VERSION 5.7 ;
  NOWIREEXTENSIONATPIN ON ;
  DIVIDERCHAR "/" ;
  BUSBITCHARS "[]" ;
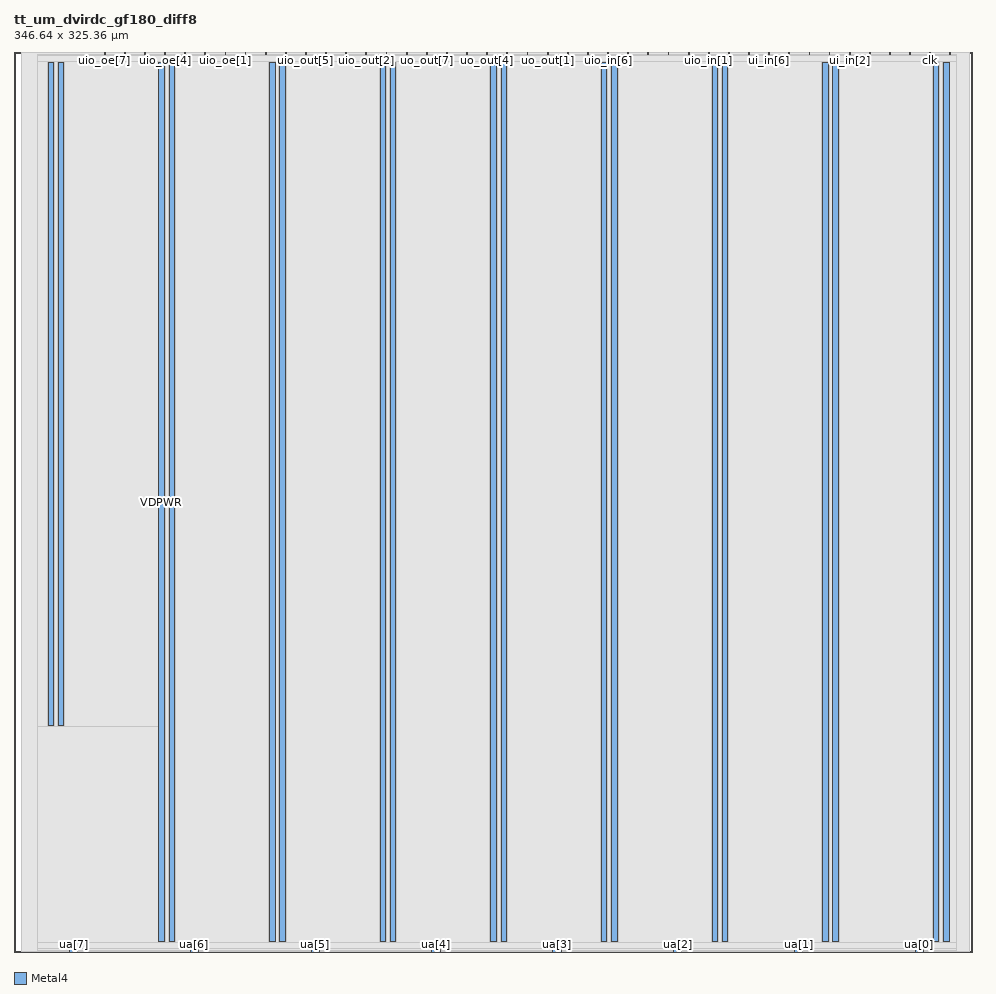
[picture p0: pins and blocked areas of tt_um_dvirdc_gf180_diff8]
MACRO tt_um_dvirdc_gf180_diff8
  CLASS BLOCK ;
  FOREIGN tt_um_dvirdc_gf180_diff8 ;
  ORIGIN 0.000 0.000 ;
  SIZE 346.640 BY 325.360 ;
  PIN VDPWR
    DIRECTION INOUT ;
    USE POWER ;
    PORT
      LAYER Metal4 ;
        RECT 12.360 81.800 14.360 321.740 ;
    END
    PORT
      LAYER Metal4 ;
        RECT 52.360 3.620 54.360 321.740 ;
    END
    PORT
      LAYER Metal4 ;
        RECT 92.360 3.620 94.360 321.740 ;
    END
    PORT
      LAYER Metal4 ;
        RECT 132.360 3.620 134.360 321.740 ;
    END
    PORT
      LAYER Metal4 ;
        RECT 172.360 3.620 174.360 321.740 ;
    END
    PORT
      LAYER Metal4 ;
        RECT 212.360 3.620 214.360 321.740 ;
    END
    PORT
      LAYER Metal4 ;
        RECT 252.360 3.620 254.360 321.740 ;
    END
    PORT
      LAYER Metal4 ;
        RECT 292.360 3.620 294.360 321.740 ;
    END
    PORT
      LAYER Metal4 ;
        RECT 332.360 3.620 334.360 321.740 ;
    END
  END VDPWR
  PIN VGND
    DIRECTION INOUT ;
    USE GROUND ;
    PORT
      LAYER Metal4 ;
        RECT 16.060 81.800 18.060 321.740 ;
    END
    PORT
      LAYER Metal4 ;
        RECT 56.060 3.620 58.060 321.740 ;
    END
    PORT
      LAYER Metal4 ;
        RECT 96.060 3.620 98.060 321.740 ;
    END
    PORT
      LAYER Metal4 ;
        RECT 136.060 3.620 138.060 321.740 ;
    END
    PORT
      LAYER Metal4 ;
        RECT 176.060 3.620 178.060 321.740 ;
    END
    PORT
      LAYER Metal4 ;
        RECT 216.060 3.620 218.060 321.740 ;
    END
    PORT
      LAYER Metal4 ;
        RECT 256.060 3.620 258.060 321.740 ;
    END
    PORT
      LAYER Metal4 ;
        RECT 296.060 3.620 298.060 321.740 ;
    END
    PORT
      LAYER Metal4 ;
        RECT 336.060 3.620 338.060 321.740 ;
    END
  END VGND
  PIN clk
    DIRECTION INPUT ;
    USE SIGNAL ;
    ANTENNAGATEAREA 0.726000 ;
    PORT
      LAYER Metal4 ;
        RECT 331.090 324.360 331.390 325.360 ;
    END
  END clk
  PIN ena
    DIRECTION INPUT ;
    USE SIGNAL ;
    ANTENNAGATEAREA 0.498500 ;
    PORT
      LAYER Metal4 ;
        RECT 338.370 324.360 338.670 325.360 ;
    END
  END ena
  PIN rst_n
    DIRECTION INPUT ;
    USE SIGNAL ;
    ANTENNAGATEAREA 0.498500 ;
    PORT
      LAYER Metal4 ;
        RECT 323.810 324.360 324.110 325.360 ;
    END
  END rst_n
  PIN ua[0]
    DIRECTION INOUT ;
    USE SIGNAL ;
    PORT
      LAYER Metal4 ;
        RECT 325.820 0.000 328.820 1.000 ;
    END
  END ua[0]
  PIN ua[1]
    DIRECTION INOUT ;
    USE SIGNAL ;
    PORT
      LAYER Metal4 ;
        RECT 282.140 0.000 285.140 1.000 ;
    END
  END ua[1]
  PIN ua[2]
    DIRECTION INOUT ;
    USE SIGNAL ;
    ANTENNAGATEAREA 24.000000 ;
    PORT
      LAYER Metal4 ;
        RECT 238.460 0.000 241.460 1.000 ;
    END
  END ua[2]
  PIN ua[3]
    DIRECTION INOUT ;
    USE SIGNAL ;
    ANTENNAGATEAREA 24.000000 ;
    PORT
      LAYER Metal4 ;
        RECT 194.780 0.000 197.780 1.000 ;
    END
  END ua[3]
  PIN ua[4]
    DIRECTION INOUT ;
    USE SIGNAL ;
    PORT
      LAYER Metal4 ;
        RECT 151.100 0.000 154.100 1.000 ;
    END
  END ua[4]
  PIN ua[5]
    DIRECTION INOUT ;
    USE SIGNAL ;
    PORT
      LAYER Metal4 ;
        RECT 107.420 0.000 110.420 1.000 ;
    END
  END ua[5]
  PIN ua[6]
    DIRECTION INOUT ;
    USE SIGNAL ;
    PORT
      LAYER Metal4 ;
        RECT 63.740 0.000 66.740 1.000 ;
    END
  END ua[6]
  PIN ua[7]
    DIRECTION INOUT ;
    USE SIGNAL ;
    PORT
      LAYER Metal4 ;
        RECT 20.060 0.000 23.060 1.000 ;
    END
  END ua[7]
  PIN ui_in[0]
    DIRECTION INPUT ;
    USE SIGNAL ;
    ANTENNAGATEAREA 0.498500 ;
    PORT
      LAYER Metal4 ;
        RECT 316.530 324.360 316.830 325.360 ;
    END
  END ui_in[0]
  PIN ui_in[1]
    DIRECTION INPUT ;
    USE SIGNAL ;
    ANTENNAGATEAREA 0.498500 ;
    PORT
      LAYER Metal4 ;
        RECT 309.250 324.360 309.550 325.360 ;
    END
  END ui_in[1]
  PIN ui_in[2]
    DIRECTION INPUT ;
    USE SIGNAL ;
    ANTENNAGATEAREA 0.498500 ;
    PORT
      LAYER Metal4 ;
        RECT 301.970 324.360 302.270 325.360 ;
    END
  END ui_in[2]
  PIN ui_in[3]
    DIRECTION INPUT ;
    USE SIGNAL ;
    PORT
      LAYER Metal4 ;
        RECT 294.690 324.360 294.990 325.360 ;
    END
  END ui_in[3]
  PIN ui_in[4]
    DIRECTION INPUT ;
    USE SIGNAL ;
    PORT
      LAYER Metal4 ;
        RECT 287.410 324.360 287.710 325.360 ;
    END
  END ui_in[4]
  PIN ui_in[5]
    DIRECTION INPUT ;
    USE SIGNAL ;
    PORT
      LAYER Metal4 ;
        RECT 280.130 324.360 280.430 325.360 ;
    END
  END ui_in[5]
  PIN ui_in[6]
    DIRECTION INPUT ;
    USE SIGNAL ;
    PORT
      LAYER Metal4 ;
        RECT 272.850 324.360 273.150 325.360 ;
    END
  END ui_in[6]
  PIN ui_in[7]
    DIRECTION INPUT ;
    USE SIGNAL ;
    PORT
      LAYER Metal4 ;
        RECT 265.570 324.360 265.870 325.360 ;
    END
  END ui_in[7]
  PIN uio_in[0]
    DIRECTION INPUT ;
    USE SIGNAL ;
    PORT
      LAYER Metal4 ;
        RECT 258.290 324.360 258.590 325.360 ;
    END
  END uio_in[0]
  PIN uio_in[1]
    DIRECTION INPUT ;
    USE SIGNAL ;
    PORT
      LAYER Metal4 ;
        RECT 251.010 324.360 251.310 325.360 ;
    END
  END uio_in[1]
  PIN uio_in[2]
    DIRECTION INPUT ;
    USE SIGNAL ;
    PORT
      LAYER Metal4 ;
        RECT 243.730 324.360 244.030 325.360 ;
    END
  END uio_in[2]
  PIN uio_in[3]
    DIRECTION INPUT ;
    USE SIGNAL ;
    PORT
      LAYER Metal4 ;
        RECT 236.450 324.360 236.750 325.360 ;
    END
  END uio_in[3]
  PIN uio_in[4]
    DIRECTION INPUT ;
    USE SIGNAL ;
    PORT
      LAYER Metal4 ;
        RECT 229.170 324.360 229.470 325.360 ;
    END
  END uio_in[4]
  PIN uio_in[5]
    DIRECTION INPUT ;
    USE SIGNAL ;
    PORT
      LAYER Metal4 ;
        RECT 221.890 324.360 222.190 325.360 ;
    END
  END uio_in[5]
  PIN uio_in[6]
    DIRECTION INPUT ;
    USE SIGNAL ;
    PORT
      LAYER Metal4 ;
        RECT 214.610 324.360 214.910 325.360 ;
    END
  END uio_in[6]
  PIN uio_in[7]
    DIRECTION INPUT ;
    USE SIGNAL ;
    PORT
      LAYER Metal4 ;
        RECT 207.330 324.360 207.630 325.360 ;
    END
  END uio_in[7]
  PIN uio_oe[0]
    DIRECTION OUTPUT ;
    USE SIGNAL ;
    ANTENNADIFFAREA 0.536800 ;
    PORT
      LAYER Metal4 ;
        RECT 83.570 324.360 83.870 325.360 ;
    END
  END uio_oe[0]
  PIN uio_oe[1]
    DIRECTION OUTPUT ;
    USE SIGNAL ;
    ANTENNADIFFAREA 0.360800 ;
    PORT
      LAYER Metal4 ;
        RECT 76.290 324.360 76.590 325.360 ;
    END
  END uio_oe[1]
  PIN uio_oe[2]
    DIRECTION OUTPUT ;
    USE SIGNAL ;
    ANTENNADIFFAREA 0.360800 ;
    PORT
      LAYER Metal4 ;
        RECT 69.010 324.360 69.310 325.360 ;
    END
  END uio_oe[2]
  PIN uio_oe[3]
    DIRECTION OUTPUT ;
    USE SIGNAL ;
    ANTENNADIFFAREA 0.360800 ;
    PORT
      LAYER Metal4 ;
        RECT 61.730 324.360 62.030 325.360 ;
    END
  END uio_oe[3]
  PIN uio_oe[4]
    DIRECTION OUTPUT ;
    USE SIGNAL ;
    ANTENNADIFFAREA 0.360800 ;
    PORT
      LAYER Metal4 ;
        RECT 54.450 324.360 54.750 325.360 ;
    END
  END uio_oe[4]
  PIN uio_oe[5]
    DIRECTION OUTPUT ;
    USE SIGNAL ;
    ANTENNADIFFAREA 0.360800 ;
    PORT
      LAYER Metal4 ;
        RECT 47.170 324.360 47.470 325.360 ;
    END
  END uio_oe[5]
  PIN uio_oe[6]
    DIRECTION OUTPUT ;
    USE SIGNAL ;
    ANTENNADIFFAREA 0.360800 ;
    PORT
      LAYER Metal4 ;
        RECT 39.890 324.360 40.190 325.360 ;
    END
  END uio_oe[6]
  PIN uio_oe[7]
    DIRECTION OUTPUT ;
    USE SIGNAL ;
    ANTENNADIFFAREA 0.360800 ;
    PORT
      LAYER Metal4 ;
        RECT 32.610 324.360 32.910 325.360 ;
    END
  END uio_oe[7]
  PIN uio_out[0]
    DIRECTION OUTPUT ;
    USE SIGNAL ;
    ANTENNADIFFAREA 0.897600 ;
    PORT
      LAYER Metal4 ;
        RECT 141.810 324.360 142.110 325.360 ;
    END
  END uio_out[0]
  PIN uio_out[1]
    DIRECTION OUTPUT ;
    USE SIGNAL ;
    ANTENNADIFFAREA 0.360800 ;
    PORT
      LAYER Metal4 ;
        RECT 134.530 324.360 134.830 325.360 ;
    END
  END uio_out[1]
  PIN uio_out[2]
    DIRECTION OUTPUT ;
    USE SIGNAL ;
    ANTENNADIFFAREA 0.360800 ;
    PORT
      LAYER Metal4 ;
        RECT 127.250 324.360 127.550 325.360 ;
    END
  END uio_out[2]
  PIN uio_out[3]
    DIRECTION OUTPUT ;
    USE SIGNAL ;
    ANTENNADIFFAREA 0.360800 ;
    PORT
      LAYER Metal4 ;
        RECT 119.970 324.360 120.270 325.360 ;
    END
  END uio_out[3]
  PIN uio_out[4]
    DIRECTION OUTPUT ;
    USE SIGNAL ;
    ANTENNADIFFAREA 0.360800 ;
    PORT
      LAYER Metal4 ;
        RECT 112.690 324.360 112.990 325.360 ;
    END
  END uio_out[4]
  PIN uio_out[5]
    DIRECTION OUTPUT ;
    USE SIGNAL ;
    ANTENNADIFFAREA 0.360800 ;
    PORT
      LAYER Metal4 ;
        RECT 105.410 324.360 105.710 325.360 ;
    END
  END uio_out[5]
  PIN uio_out[6]
    DIRECTION OUTPUT ;
    USE SIGNAL ;
    ANTENNADIFFAREA 0.360800 ;
    PORT
      LAYER Metal4 ;
        RECT 98.130 324.360 98.430 325.360 ;
    END
  END uio_out[6]
  PIN uio_out[7]
    DIRECTION OUTPUT ;
    USE SIGNAL ;
    ANTENNADIFFAREA 0.360800 ;
    PORT
      LAYER Metal4 ;
        RECT 90.850 324.360 91.150 325.360 ;
    END
  END uio_out[7]
  PIN uo_out[0]
    DIRECTION OUTPUT ;
    USE SIGNAL ;
    ANTENNADIFFAREA 0.897600 ;
    PORT
      LAYER Metal4 ;
        RECT 200.050 324.360 200.350 325.360 ;
    END
  END uo_out[0]
  PIN uo_out[1]
    DIRECTION OUTPUT ;
    USE SIGNAL ;
    ANTENNADIFFAREA 0.897600 ;
    PORT
      LAYER Metal4 ;
        RECT 192.770 324.360 193.070 325.360 ;
    END
  END uo_out[1]
  PIN uo_out[2]
    DIRECTION OUTPUT ;
    USE SIGNAL ;
    ANTENNADIFFAREA 0.897600 ;
    PORT
      LAYER Metal4 ;
        RECT 185.490 324.360 185.790 325.360 ;
    END
  END uo_out[2]
  PIN uo_out[3]
    DIRECTION OUTPUT ;
    USE SIGNAL ;
    ANTENNADIFFAREA 0.897600 ;
    PORT
      LAYER Metal4 ;
        RECT 178.210 324.360 178.510 325.360 ;
    END
  END uo_out[3]
  PIN uo_out[4]
    DIRECTION OUTPUT ;
    USE SIGNAL ;
    ANTENNADIFFAREA 0.897600 ;
    PORT
      LAYER Metal4 ;
        RECT 170.930 324.360 171.230 325.360 ;
    END
  END uo_out[4]
  PIN uo_out[5]
    DIRECTION OUTPUT ;
    USE SIGNAL ;
    ANTENNADIFFAREA 0.897600 ;
    PORT
      LAYER Metal4 ;
        RECT 163.650 324.360 163.950 325.360 ;
    END
  END uo_out[5]
  PIN uo_out[6]
    DIRECTION OUTPUT ;
    USE SIGNAL ;
    ANTENNADIFFAREA 0.897600 ;
    PORT
      LAYER Metal4 ;
        RECT 156.370 324.360 156.670 325.360 ;
    END
  END uo_out[6]
  PIN uo_out[7]
    DIRECTION OUTPUT ;
    USE SIGNAL ;
    ANTENNADIFFAREA 0.897600 ;
    PORT
      LAYER Metal4 ;
        RECT 149.090 324.360 149.390 325.360 ;
    END
  END uo_out[7]
  OBS
      LAYER Nwell ;
        RECT 2.930 3.490 343.710 321.870 ;
      LAYER Metal1 ;
        RECT 3.360 3.620 343.280 321.740 ;
      LAYER Metal2 ;
        RECT 2.940 0.090 345.380 325.270 ;
      LAYER Metal3 ;
        RECT 2.890 0.140 345.430 325.220 ;
      LAYER Metal4 ;
        RECT 8.540 324.060 32.310 324.360 ;
        RECT 33.210 324.060 39.590 324.360 ;
        RECT 40.490 324.060 46.870 324.360 ;
        RECT 47.770 324.060 54.150 324.360 ;
        RECT 55.050 324.060 61.430 324.360 ;
        RECT 62.330 324.060 68.710 324.360 ;
        RECT 69.610 324.060 75.990 324.360 ;
        RECT 76.890 324.060 83.270 324.360 ;
        RECT 84.170 324.060 90.550 324.360 ;
        RECT 91.450 324.060 97.830 324.360 ;
        RECT 98.730 324.060 105.110 324.360 ;
        RECT 106.010 324.060 112.390 324.360 ;
        RECT 113.290 324.060 119.670 324.360 ;
        RECT 120.570 324.060 126.950 324.360 ;
        RECT 127.850 324.060 134.230 324.360 ;
        RECT 135.130 324.060 141.510 324.360 ;
        RECT 142.410 324.060 148.790 324.360 ;
        RECT 149.690 324.060 156.070 324.360 ;
        RECT 156.970 324.060 163.350 324.360 ;
        RECT 164.250 324.060 170.630 324.360 ;
        RECT 171.530 324.060 177.910 324.360 ;
        RECT 178.810 324.060 185.190 324.360 ;
        RECT 186.090 324.060 192.470 324.360 ;
        RECT 193.370 324.060 199.750 324.360 ;
        RECT 200.650 324.060 207.030 324.360 ;
        RECT 207.930 324.060 214.310 324.360 ;
        RECT 215.210 324.060 221.590 324.360 ;
        RECT 222.490 324.060 228.870 324.360 ;
        RECT 229.770 324.060 236.150 324.360 ;
        RECT 237.050 324.060 243.430 324.360 ;
        RECT 244.330 324.060 250.710 324.360 ;
        RECT 251.610 324.060 257.990 324.360 ;
        RECT 258.890 324.060 265.270 324.360 ;
        RECT 266.170 324.060 272.550 324.360 ;
        RECT 273.450 324.060 279.830 324.360 ;
        RECT 280.730 324.060 287.110 324.360 ;
        RECT 288.010 324.060 294.390 324.360 ;
        RECT 295.290 324.060 301.670 324.360 ;
        RECT 302.570 324.060 308.950 324.360 ;
        RECT 309.850 324.060 316.230 324.360 ;
        RECT 317.130 324.060 323.510 324.360 ;
        RECT 324.410 324.060 330.790 324.360 ;
        RECT 331.690 324.060 338.070 324.360 ;
        RECT 338.970 324.060 340.900 324.360 ;
        RECT 8.540 322.040 340.900 324.060 ;
        RECT 8.540 81.500 12.060 322.040 ;
        RECT 14.660 81.500 15.760 322.040 ;
        RECT 18.360 81.500 52.060 322.040 ;
        RECT 8.540 3.320 52.060 81.500 ;
        RECT 54.660 3.320 55.760 322.040 ;
        RECT 58.360 3.320 92.060 322.040 ;
        RECT 94.660 3.320 95.760 322.040 ;
        RECT 98.360 3.320 132.060 322.040 ;
        RECT 134.660 3.320 135.760 322.040 ;
        RECT 138.360 3.320 172.060 322.040 ;
        RECT 174.660 3.320 175.760 322.040 ;
        RECT 178.360 3.320 212.060 322.040 ;
        RECT 214.660 3.320 215.760 322.040 ;
        RECT 218.360 3.320 252.060 322.040 ;
        RECT 254.660 3.320 255.760 322.040 ;
        RECT 258.360 3.320 292.060 322.040 ;
        RECT 294.660 3.320 295.760 322.040 ;
        RECT 298.360 3.320 332.060 322.040 ;
        RECT 334.660 3.320 335.760 322.040 ;
        RECT 338.360 3.320 340.900 322.040 ;
        RECT 8.540 1.300 340.900 3.320 ;
        RECT 8.540 0.650 19.760 1.300 ;
        RECT 23.360 0.650 63.440 1.300 ;
        RECT 67.040 0.650 107.120 1.300 ;
        RECT 110.720 0.650 150.800 1.300 ;
        RECT 154.400 0.650 194.480 1.300 ;
        RECT 198.080 0.650 238.160 1.300 ;
        RECT 241.760 0.650 281.840 1.300 ;
        RECT 285.440 0.650 325.520 1.300 ;
        RECT 329.120 0.650 340.900 1.300 ;
  END
END tt_um_dvirdc_gf180_diff8
END LIBRARY

